##
## LEF for PtnCells ;
## created by Innovus v15.23-s045_1 on Wed Mar 11 08:48:27 2026
##

VERSION 5.8 ;

BUSBITCHARS "[]" ;
DIVIDERCHAR "/" ;

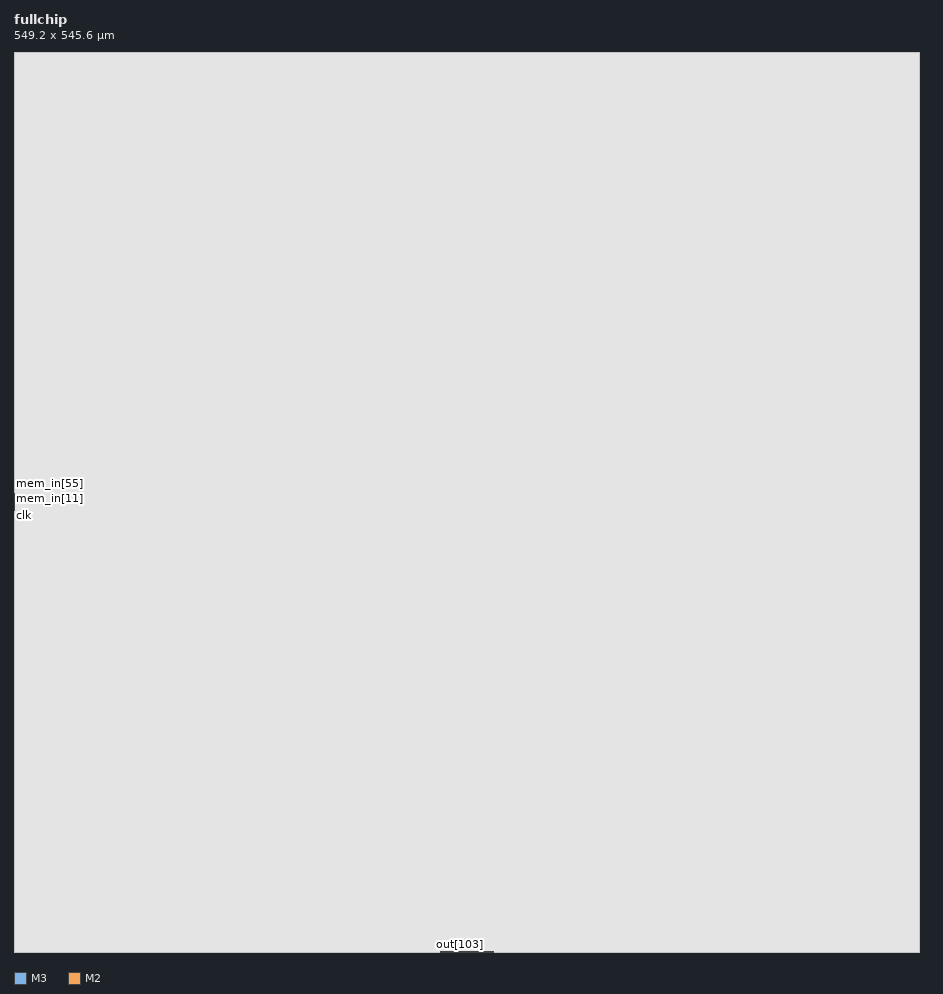
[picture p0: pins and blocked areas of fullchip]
MACRO fullchip
  CLASS BLOCK ;
  SIZE 549.2000 BY 545.6000 ;
  FOREIGN fullchip 0.0000 0.0000 ;
  ORIGIN 0 0 ;
  SYMMETRY X Y R90 ;
  PIN clk
    DIRECTION INPUT ;
    USE SIGNAL ;
    PORT
      LAYER M3 ;
        RECT 0.0000 264.3500 0.5000 264.4500 ;
    END
  END clk
  PIN mem_in[63]
    DIRECTION INPUT ;
    USE SIGNAL ;
    PORT
      LAYER M3 ;
        RECT 0.0000 280.9500 0.5000 281.0500 ;
    END
  END mem_in[63]
  PIN mem_in[62]
    DIRECTION INPUT ;
    USE SIGNAL ;
    PORT
      LAYER M3 ;
        RECT 0.0000 280.7500 0.5000 280.8500 ;
    END
  END mem_in[62]
  PIN mem_in[61]
    DIRECTION INPUT ;
    USE SIGNAL ;
    PORT
      LAYER M3 ;
        RECT 0.0000 280.5500 0.5000 280.6500 ;
    END
  END mem_in[61]
  PIN mem_in[60]
    DIRECTION INPUT ;
    USE SIGNAL ;
    PORT
      LAYER M3 ;
        RECT 0.0000 280.3500 0.5000 280.4500 ;
    END
  END mem_in[60]
  PIN mem_in[59]
    DIRECTION INPUT ;
    USE SIGNAL ;
    PORT
      LAYER M3 ;
        RECT 0.0000 280.1500 0.5000 280.2500 ;
    END
  END mem_in[59]
  PIN mem_in[58]
    DIRECTION INPUT ;
    USE SIGNAL ;
    PORT
      LAYER M3 ;
        RECT 0.0000 279.9500 0.5000 280.0500 ;
    END
  END mem_in[58]
  PIN mem_in[57]
    DIRECTION INPUT ;
    USE SIGNAL ;
    PORT
      LAYER M3 ;
        RECT 0.0000 279.7500 0.5000 279.8500 ;
    END
  END mem_in[57]
  PIN mem_in[56]
    DIRECTION INPUT ;
    USE SIGNAL ;
    PORT
      LAYER M3 ;
        RECT 0.0000 279.5500 0.5000 279.6500 ;
    END
  END mem_in[56]
  PIN mem_in[55]
    DIRECTION INPUT ;
    USE SIGNAL ;
    PORT
      LAYER M3 ;
        RECT 0.0000 279.3500 0.5000 279.4500 ;
    END
  END mem_in[55]
  PIN mem_in[54]
    DIRECTION INPUT ;
    USE SIGNAL ;
    PORT
      LAYER M3 ;
        RECT 0.0000 279.1500 0.5000 279.2500 ;
    END
  END mem_in[54]
  PIN mem_in[53]
    DIRECTION INPUT ;
    USE SIGNAL ;
    PORT
      LAYER M3 ;
        RECT 0.0000 278.9500 0.5000 279.0500 ;
    END
  END mem_in[53]
  PIN mem_in[52]
    DIRECTION INPUT ;
    USE SIGNAL ;
    PORT
      LAYER M3 ;
        RECT 0.0000 278.7500 0.5000 278.8500 ;
    END
  END mem_in[52]
  PIN mem_in[51]
    DIRECTION INPUT ;
    USE SIGNAL ;
    PORT
      LAYER M3 ;
        RECT 0.0000 278.5500 0.5000 278.6500 ;
    END
  END mem_in[51]
  PIN mem_in[50]
    DIRECTION INPUT ;
    USE SIGNAL ;
    PORT
      LAYER M3 ;
        RECT 0.0000 278.3500 0.5000 278.4500 ;
    END
  END mem_in[50]
  PIN mem_in[49]
    DIRECTION INPUT ;
    USE SIGNAL ;
    PORT
      LAYER M3 ;
        RECT 0.0000 278.1500 0.5000 278.2500 ;
    END
  END mem_in[49]
  PIN mem_in[48]
    DIRECTION INPUT ;
    USE SIGNAL ;
    PORT
      LAYER M3 ;
        RECT 0.0000 277.9500 0.5000 278.0500 ;
    END
  END mem_in[48]
  PIN mem_in[47]
    DIRECTION INPUT ;
    USE SIGNAL ;
    PORT
      LAYER M3 ;
        RECT 0.0000 277.7500 0.5000 277.8500 ;
    END
  END mem_in[47]
  PIN mem_in[46]
    DIRECTION INPUT ;
    USE SIGNAL ;
    PORT
      LAYER M3 ;
        RECT 0.0000 277.5500 0.5000 277.6500 ;
    END
  END mem_in[46]
  PIN mem_in[45]
    DIRECTION INPUT ;
    USE SIGNAL ;
    PORT
      LAYER M3 ;
        RECT 0.0000 277.3500 0.5000 277.4500 ;
    END
  END mem_in[45]
  PIN mem_in[44]
    DIRECTION INPUT ;
    USE SIGNAL ;
    PORT
      LAYER M3 ;
        RECT 0.0000 277.1500 0.5000 277.2500 ;
    END
  END mem_in[44]
  PIN mem_in[43]
    DIRECTION INPUT ;
    USE SIGNAL ;
    PORT
      LAYER M3 ;
        RECT 0.0000 276.9500 0.5000 277.0500 ;
    END
  END mem_in[43]
  PIN mem_in[42]
    DIRECTION INPUT ;
    USE SIGNAL ;
    PORT
      LAYER M3 ;
        RECT 0.0000 276.7500 0.5000 276.8500 ;
    END
  END mem_in[42]
  PIN mem_in[41]
    DIRECTION INPUT ;
    USE SIGNAL ;
    PORT
      LAYER M3 ;
        RECT 0.0000 276.5500 0.5000 276.6500 ;
    END
  END mem_in[41]
  PIN mem_in[40]
    DIRECTION INPUT ;
    USE SIGNAL ;
    PORT
      LAYER M3 ;
        RECT 0.0000 276.3500 0.5000 276.4500 ;
    END
  END mem_in[40]
  PIN mem_in[39]
    DIRECTION INPUT ;
    USE SIGNAL ;
    PORT
      LAYER M3 ;
        RECT 0.0000 276.1500 0.5000 276.2500 ;
    END
  END mem_in[39]
  PIN mem_in[38]
    DIRECTION INPUT ;
    USE SIGNAL ;
    PORT
      LAYER M3 ;
        RECT 0.0000 275.9500 0.5000 276.0500 ;
    END
  END mem_in[38]
  PIN mem_in[37]
    DIRECTION INPUT ;
    USE SIGNAL ;
    PORT
      LAYER M3 ;
        RECT 0.0000 275.5500 0.5000 275.6500 ;
    END
  END mem_in[37]
  PIN mem_in[36]
    DIRECTION INPUT ;
    USE SIGNAL ;
    PORT
      LAYER M3 ;
        RECT 0.0000 275.3500 0.5000 275.4500 ;
    END
  END mem_in[36]
  PIN mem_in[35]
    DIRECTION INPUT ;
    USE SIGNAL ;
    PORT
      LAYER M3 ;
        RECT 0.0000 275.1500 0.5000 275.2500 ;
    END
  END mem_in[35]
  PIN mem_in[34]
    DIRECTION INPUT ;
    USE SIGNAL ;
    PORT
      LAYER M3 ;
        RECT 0.0000 274.9500 0.5000 275.0500 ;
    END
  END mem_in[34]
  PIN mem_in[33]
    DIRECTION INPUT ;
    USE SIGNAL ;
    PORT
      LAYER M3 ;
        RECT 0.0000 274.7500 0.5000 274.8500 ;
    END
  END mem_in[33]
  PIN mem_in[32]
    DIRECTION INPUT ;
    USE SIGNAL ;
    PORT
      LAYER M3 ;
        RECT 0.0000 274.5500 0.5000 274.6500 ;
    END
  END mem_in[32]
  PIN mem_in[31]
    DIRECTION INPUT ;
    USE SIGNAL ;
    PORT
      LAYER M3 ;
        RECT 0.0000 274.3500 0.5000 274.4500 ;
    END
  END mem_in[31]
  PIN mem_in[30]
    DIRECTION INPUT ;
    USE SIGNAL ;
    PORT
      LAYER M3 ;
        RECT 0.0000 274.1500 0.5000 274.2500 ;
    END
  END mem_in[30]
  PIN mem_in[29]
    DIRECTION INPUT ;
    USE SIGNAL ;
    PORT
      LAYER M3 ;
        RECT 0.0000 273.9500 0.5000 274.0500 ;
    END
  END mem_in[29]
  PIN mem_in[28]
    DIRECTION INPUT ;
    USE SIGNAL ;
    PORT
      LAYER M3 ;
        RECT 0.0000 273.7500 0.5000 273.8500 ;
    END
  END mem_in[28]
  PIN mem_in[27]
    DIRECTION INPUT ;
    USE SIGNAL ;
    PORT
      LAYER M3 ;
        RECT 0.0000 273.5500 0.5000 273.6500 ;
    END
  END mem_in[27]
  PIN mem_in[26]
    DIRECTION INPUT ;
    USE SIGNAL ;
    PORT
      LAYER M3 ;
        RECT 0.0000 273.3500 0.5000 273.4500 ;
    END
  END mem_in[26]
  PIN mem_in[25]
    DIRECTION INPUT ;
    USE SIGNAL ;
    PORT
      LAYER M3 ;
        RECT 0.0000 273.1500 0.5000 273.2500 ;
    END
  END mem_in[25]
  PIN mem_in[24]
    DIRECTION INPUT ;
    USE SIGNAL ;
    PORT
      LAYER M3 ;
        RECT 0.0000 272.9500 0.5000 273.0500 ;
    END
  END mem_in[24]
  PIN mem_in[23]
    DIRECTION INPUT ;
    USE SIGNAL ;
    PORT
      LAYER M3 ;
        RECT 0.0000 272.7500 0.5000 272.8500 ;
    END
  END mem_in[23]
  PIN mem_in[22]
    DIRECTION INPUT ;
    USE SIGNAL ;
    PORT
      LAYER M3 ;
        RECT 0.0000 272.5500 0.5000 272.6500 ;
    END
  END mem_in[22]
  PIN mem_in[21]
    DIRECTION INPUT ;
    USE SIGNAL ;
    PORT
      LAYER M3 ;
        RECT 0.0000 272.3500 0.5000 272.4500 ;
    END
  END mem_in[21]
  PIN mem_in[20]
    DIRECTION INPUT ;
    USE SIGNAL ;
    PORT
      LAYER M3 ;
        RECT 0.0000 272.1500 0.5000 272.2500 ;
    END
  END mem_in[20]
  PIN mem_in[19]
    DIRECTION INPUT ;
    USE SIGNAL ;
    PORT
      LAYER M3 ;
        RECT 0.0000 271.9500 0.5000 272.0500 ;
    END
  END mem_in[19]
  PIN mem_in[18]
    DIRECTION INPUT ;
    USE SIGNAL ;
    PORT
      LAYER M3 ;
        RECT 0.0000 271.7500 0.5000 271.8500 ;
    END
  END mem_in[18]
  PIN mem_in[17]
    DIRECTION INPUT ;
    USE SIGNAL ;
    PORT
      LAYER M3 ;
        RECT 0.0000 271.5500 0.5000 271.6500 ;
    END
  END mem_in[17]
  PIN mem_in[16]
    DIRECTION INPUT ;
    USE SIGNAL ;
    PORT
      LAYER M3 ;
        RECT 0.0000 271.3500 0.5000 271.4500 ;
    END
  END mem_in[16]
  PIN mem_in[15]
    DIRECTION INPUT ;
    USE SIGNAL ;
    PORT
      LAYER M3 ;
        RECT 0.0000 271.1500 0.5000 271.2500 ;
    END
  END mem_in[15]
  PIN mem_in[14]
    DIRECTION INPUT ;
    USE SIGNAL ;
    PORT
      LAYER M3 ;
        RECT 0.0000 270.9500 0.5000 271.0500 ;
    END
  END mem_in[14]
  PIN mem_in[13]
    DIRECTION INPUT ;
    USE SIGNAL ;
    PORT
      LAYER M3 ;
        RECT 0.0000 270.7500 0.5000 270.8500 ;
    END
  END mem_in[13]
  PIN mem_in[12]
    DIRECTION INPUT ;
    USE SIGNAL ;
    PORT
      LAYER M3 ;
        RECT 0.0000 270.5500 0.5000 270.6500 ;
    END
  END mem_in[12]
  PIN mem_in[11]
    DIRECTION INPUT ;
    USE SIGNAL ;
    PORT
      LAYER M3 ;
        RECT 0.0000 270.3500 0.5000 270.4500 ;
    END
  END mem_in[11]
  PIN mem_in[10]
    DIRECTION INPUT ;
    USE SIGNAL ;
    PORT
      LAYER M3 ;
        RECT 0.0000 270.1500 0.5000 270.2500 ;
    END
  END mem_in[10]
  PIN mem_in[9]
    DIRECTION INPUT ;
    USE SIGNAL ;
    PORT
      LAYER M3 ;
        RECT 0.0000 269.9500 0.5000 270.0500 ;
    END
  END mem_in[9]
  PIN mem_in[8]
    DIRECTION INPUT ;
    USE SIGNAL ;
    PORT
      LAYER M3 ;
        RECT 0.0000 269.7500 0.5000 269.8500 ;
    END
  END mem_in[8]
  PIN mem_in[7]
    DIRECTION INPUT ;
    USE SIGNAL ;
    PORT
      LAYER M3 ;
        RECT 0.0000 269.5500 0.5000 269.6500 ;
    END
  END mem_in[7]
  PIN mem_in[6]
    DIRECTION INPUT ;
    USE SIGNAL ;
    PORT
      LAYER M3 ;
        RECT 0.0000 269.3500 0.5000 269.4500 ;
    END
  END mem_in[6]
  PIN mem_in[5]
    DIRECTION INPUT ;
    USE SIGNAL ;
    PORT
      LAYER M3 ;
        RECT 0.0000 269.1500 0.5000 269.2500 ;
    END
  END mem_in[5]
  PIN mem_in[4]
    DIRECTION INPUT ;
    USE SIGNAL ;
    PORT
      LAYER M3 ;
        RECT 0.0000 268.9500 0.5000 269.0500 ;
    END
  END mem_in[4]
  PIN mem_in[3]
    DIRECTION INPUT ;
    USE SIGNAL ;
    PORT
      LAYER M3 ;
        RECT 0.0000 268.7500 0.5000 268.8500 ;
    END
  END mem_in[3]
  PIN mem_in[2]
    DIRECTION INPUT ;
    USE SIGNAL ;
    PORT
      LAYER M3 ;
        RECT 0.0000 268.5500 0.5000 268.6500 ;
    END
  END mem_in[2]
  PIN mem_in[1]
    DIRECTION INPUT ;
    USE SIGNAL ;
    PORT
      LAYER M3 ;
        RECT 0.0000 268.3500 0.5000 268.4500 ;
    END
  END mem_in[1]
  PIN mem_in[0]
    DIRECTION INPUT ;
    USE SIGNAL ;
    PORT
      LAYER M3 ;
        RECT 0.0000 268.1500 0.5000 268.2500 ;
    END
  END mem_in[0]
  PIN inst[16]
    DIRECTION INPUT ;
    USE SIGNAL ;
    PORT
      LAYER M3 ;
        RECT 0.0000 267.9500 0.5000 268.0500 ;
    END
  END inst[16]
  PIN inst[15]
    DIRECTION INPUT ;
    USE SIGNAL ;
    PORT
      LAYER M3 ;
        RECT 0.0000 267.7500 0.5000 267.8500 ;
    END
  END inst[15]
  PIN inst[14]
    DIRECTION INPUT ;
    USE SIGNAL ;
    PORT
      LAYER M3 ;
        RECT 0.0000 267.5500 0.5000 267.6500 ;
    END
  END inst[14]
  PIN inst[13]
    DIRECTION INPUT ;
    USE SIGNAL ;
    PORT
      LAYER M3 ;
        RECT 0.0000 267.3500 0.5000 267.4500 ;
    END
  END inst[13]
  PIN inst[12]
    DIRECTION INPUT ;
    USE SIGNAL ;
    PORT
      LAYER M3 ;
        RECT 0.0000 267.1500 0.5000 267.2500 ;
    END
  END inst[12]
  PIN inst[11]
    DIRECTION INPUT ;
    USE SIGNAL ;
    PORT
      LAYER M3 ;
        RECT 0.0000 266.9500 0.5000 267.0500 ;
    END
  END inst[11]
  PIN inst[10]
    DIRECTION INPUT ;
    USE SIGNAL ;
    PORT
      LAYER M3 ;
        RECT 0.0000 266.7500 0.5000 266.8500 ;
    END
  END inst[10]
  PIN inst[9]
    DIRECTION INPUT ;
    USE SIGNAL ;
    PORT
      LAYER M3 ;
        RECT 0.0000 266.5500 0.5000 266.6500 ;
    END
  END inst[9]
  PIN inst[8]
    DIRECTION INPUT ;
    USE SIGNAL ;
    PORT
      LAYER M3 ;
        RECT 0.0000 266.3500 0.5000 266.4500 ;
    END
  END inst[8]
  PIN inst[7]
    DIRECTION INPUT ;
    USE SIGNAL ;
    PORT
      LAYER M3 ;
        RECT 0.0000 266.1500 0.5000 266.2500 ;
    END
  END inst[7]
  PIN inst[6]
    DIRECTION INPUT ;
    USE SIGNAL ;
    PORT
      LAYER M3 ;
        RECT 0.0000 265.9500 0.5000 266.0500 ;
    END
  END inst[6]
  PIN inst[5]
    DIRECTION INPUT ;
    USE SIGNAL ;
    PORT
      LAYER M3 ;
        RECT 0.0000 265.7500 0.5000 265.8500 ;
    END
  END inst[5]
  PIN inst[4]
    DIRECTION INPUT ;
    USE SIGNAL ;
    PORT
      LAYER M3 ;
        RECT 0.0000 265.5500 0.5000 265.6500 ;
    END
  END inst[4]
  PIN inst[3]
    DIRECTION INPUT ;
    USE SIGNAL ;
    PORT
      LAYER M3 ;
        RECT 0.0000 265.3500 0.5000 265.4500 ;
    END
  END inst[3]
  PIN inst[2]
    DIRECTION INPUT ;
    USE SIGNAL ;
    PORT
      LAYER M3 ;
        RECT 0.0000 265.1500 0.5000 265.2500 ;
    END
  END inst[2]
  PIN inst[1]
    DIRECTION INPUT ;
    USE SIGNAL ;
    PORT
      LAYER M3 ;
        RECT 0.0000 264.9500 0.5000 265.0500 ;
    END
  END inst[1]
  PIN inst[0]
    DIRECTION INPUT ;
    USE SIGNAL ;
    PORT
      LAYER M3 ;
        RECT 0.0000 264.7500 0.5000 264.8500 ;
    END
  END inst[0]
  PIN reset
    DIRECTION INPUT ;
    USE SIGNAL ;
    PORT
      LAYER M3 ;
        RECT 0.0000 264.5500 0.5000 264.6500 ;
    END
  END reset
  PIN out[159]
    DIRECTION OUTPUT ;
    USE SIGNAL ;
    PORT
      LAYER M2 ;
        RECT 258.8500 0.0000 258.9500 0.5000 ;
    END
  END out[159]
  PIN out[158]
    DIRECTION OUTPUT ;
    USE SIGNAL ;
    PORT
      LAYER M2 ;
        RECT 259.0500 0.0000 259.1500 0.5000 ;
    END
  END out[158]
  PIN out[157]
    DIRECTION OUTPUT ;
    USE SIGNAL ;
    PORT
      LAYER M2 ;
        RECT 259.2500 0.0000 259.3500 0.5000 ;
    END
  END out[157]
  PIN out[156]
    DIRECTION OUTPUT ;
    USE SIGNAL ;
    PORT
      LAYER M2 ;
        RECT 259.4500 0.0000 259.5500 0.5000 ;
    END
  END out[156]
  PIN out[155]
    DIRECTION OUTPUT ;
    USE SIGNAL ;
    PORT
      LAYER M2 ;
        RECT 259.6500 0.0000 259.7500 0.5000 ;
    END
  END out[155]
  PIN out[154]
    DIRECTION OUTPUT ;
    USE SIGNAL ;
    PORT
      LAYER M2 ;
        RECT 259.8500 0.0000 259.9500 0.5000 ;
    END
  END out[154]
  PIN out[153]
    DIRECTION OUTPUT ;
    USE SIGNAL ;
    PORT
      LAYER M2 ;
        RECT 260.0500 0.0000 260.1500 0.5000 ;
    END
  END out[153]
  PIN out[152]
    DIRECTION OUTPUT ;
    USE SIGNAL ;
    PORT
      LAYER M2 ;
        RECT 260.2500 0.0000 260.3500 0.5000 ;
    END
  END out[152]
  PIN out[151]
    DIRECTION OUTPUT ;
    USE SIGNAL ;
    PORT
      LAYER M2 ;
        RECT 260.4500 0.0000 260.5500 0.5000 ;
    END
  END out[151]
  PIN out[150]
    DIRECTION OUTPUT ;
    USE SIGNAL ;
    PORT
      LAYER M2 ;
        RECT 260.6500 0.0000 260.7500 0.5000 ;
    END
  END out[150]
  PIN out[149]
    DIRECTION OUTPUT ;
    USE SIGNAL ;
    PORT
      LAYER M2 ;
        RECT 260.8500 0.0000 260.9500 0.5000 ;
    END
  END out[149]
  PIN out[148]
    DIRECTION OUTPUT ;
    USE SIGNAL ;
    PORT
      LAYER M2 ;
        RECT 261.0500 0.0000 261.1500 0.5000 ;
    END
  END out[148]
  PIN out[147]
    DIRECTION OUTPUT ;
    USE SIGNAL ;
    PORT
      LAYER M2 ;
        RECT 261.2500 0.0000 261.3500 0.5000 ;
    END
  END out[147]
  PIN out[146]
    DIRECTION OUTPUT ;
    USE SIGNAL ;
    PORT
      LAYER M2 ;
        RECT 261.4500 0.0000 261.5500 0.5000 ;
    END
  END out[146]
  PIN out[145]
    DIRECTION OUTPUT ;
    USE SIGNAL ;
    PORT
      LAYER M2 ;
        RECT 261.6500 0.0000 261.7500 0.5000 ;
    END
  END out[145]
  PIN out[144]
    DIRECTION OUTPUT ;
    USE SIGNAL ;
    PORT
      LAYER M2 ;
        RECT 261.8500 0.0000 261.9500 0.5000 ;
    END
  END out[144]
  PIN out[143]
    DIRECTION OUTPUT ;
    USE SIGNAL ;
    PORT
      LAYER M2 ;
        RECT 262.0500 0.0000 262.1500 0.5000 ;
    END
  END out[143]
  PIN out[142]
    DIRECTION OUTPUT ;
    USE SIGNAL ;
    PORT
      LAYER M2 ;
        RECT 262.2500 0.0000 262.3500 0.5000 ;
    END
  END out[142]
  PIN out[141]
    DIRECTION OUTPUT ;
    USE SIGNAL ;
    PORT
      LAYER M2 ;
        RECT 262.4500 0.0000 262.5500 0.5000 ;
    END
  END out[141]
  PIN out[140]
    DIRECTION OUTPUT ;
    USE SIGNAL ;
    PORT
      LAYER M2 ;
        RECT 262.6500 0.0000 262.7500 0.5000 ;
    END
  END out[140]
  PIN out[139]
    DIRECTION OUTPUT ;
    USE SIGNAL ;
    PORT
      LAYER M2 ;
        RECT 262.8500 0.0000 262.9500 0.5000 ;
    END
  END out[139]
  PIN out[138]
    DIRECTION OUTPUT ;
    USE SIGNAL ;
    PORT
      LAYER M2 ;
        RECT 263.0500 0.0000 263.1500 0.5000 ;
    END
  END out[138]
  PIN out[137]
    DIRECTION OUTPUT ;
    USE SIGNAL ;
    PORT
      LAYER M2 ;
        RECT 263.2500 0.0000 263.3500 0.5000 ;
    END
  END out[137]
  PIN out[136]
    DIRECTION OUTPUT ;
    USE SIGNAL ;
    PORT
      LAYER M2 ;
        RECT 263.4500 0.0000 263.5500 0.5000 ;
    END
  END out[136]
  PIN out[135]
    DIRECTION OUTPUT ;
    USE SIGNAL ;
    PORT
      LAYER M2 ;
        RECT 263.6500 0.0000 263.7500 0.5000 ;
    END
  END out[135]
  PIN out[134]
    DIRECTION OUTPUT ;
    USE SIGNAL ;
    PORT
      LAYER M2 ;
        RECT 263.8500 0.0000 263.9500 0.5000 ;
    END
  END out[134]
  PIN out[133]
    DIRECTION OUTPUT ;
    USE SIGNAL ;
    PORT
      LAYER M2 ;
        RECT 264.0500 0.0000 264.1500 0.5000 ;
    END
  END out[133]
  PIN out[132]
    DIRECTION OUTPUT ;
    USE SIGNAL ;
    PORT
      LAYER M2 ;
        RECT 264.2500 0.0000 264.3500 0.5000 ;
    END
  END out[132]
  PIN out[131]
    DIRECTION OUTPUT ;
    USE SIGNAL ;
    PORT
      LAYER M2 ;
        RECT 264.4500 0.0000 264.5500 0.5000 ;
    END
  END out[131]
  PIN out[130]
    DIRECTION OUTPUT ;
    USE SIGNAL ;
    PORT
      LAYER M2 ;
        RECT 264.6500 0.0000 264.7500 0.5000 ;
    END
  END out[130]
  PIN out[129]
    DIRECTION OUTPUT ;
    USE SIGNAL ;
    PORT
      LAYER M2 ;
        RECT 264.8500 0.0000 264.9500 0.5000 ;
    END
  END out[129]
  PIN out[128]
    DIRECTION OUTPUT ;
    USE SIGNAL ;
    PORT
      LAYER M2 ;
        RECT 265.0500 0.0000 265.1500 0.5000 ;
    END
  END out[128]
  PIN out[127]
    DIRECTION OUTPUT ;
    USE SIGNAL ;
    PORT
      LAYER M2 ;
        RECT 265.2500 0.0000 265.3500 0.5000 ;
    END
  END out[127]
  PIN out[126]
    DIRECTION OUTPUT ;
    USE SIGNAL ;
    PORT
      LAYER M2 ;
        RECT 265.4500 0.0000 265.5500 0.5000 ;
    END
  END out[126]
  PIN out[125]
    DIRECTION OUTPUT ;
    USE SIGNAL ;
    PORT
      LAYER M2 ;
        RECT 265.6500 0.0000 265.7500 0.5000 ;
    END
  END out[125]
  PIN out[124]
    DIRECTION OUTPUT ;
    USE SIGNAL ;
    PORT
      LAYER M2 ;
        RECT 265.8500 0.0000 265.9500 0.5000 ;
    END
  END out[124]
  PIN out[123]
    DIRECTION OUTPUT ;
    USE SIGNAL ;
    PORT
      LAYER M2 ;
        RECT 266.0500 0.0000 266.1500 0.5000 ;
    END
  END out[123]
  PIN out[122]
    DIRECTION OUTPUT ;
    USE SIGNAL ;
    PORT
      LAYER M2 ;
        RECT 266.2500 0.0000 266.3500 0.5000 ;
    END
  END out[122]
  PIN out[121]
    DIRECTION OUTPUT ;
    USE SIGNAL ;
    PORT
      LAYER M2 ;
        RECT 266.4500 0.0000 266.5500 0.5000 ;
    END
  END out[121]
  PIN out[120]
    DIRECTION OUTPUT ;
    USE SIGNAL ;
    PORT
      LAYER M2 ;
        RECT 266.6500 0.0000 266.7500 0.5000 ;
    END
  END out[120]
  PIN out[119]
    DIRECTION OUTPUT ;
    USE SIGNAL ;
    PORT
      LAYER M2 ;
        RECT 266.8500 0.0000 266.9500 0.5000 ;
    END
  END out[119]
  PIN out[118]
    DIRECTION OUTPUT ;
    USE SIGNAL ;
    PORT
      LAYER M2 ;
        RECT 267.0500 0.0000 267.1500 0.5000 ;
    END
  END out[118]
  PIN out[117]
    DIRECTION OUTPUT ;
    USE SIGNAL ;
    PORT
      LAYER M2 ;
        RECT 267.2500 0.0000 267.3500 0.5000 ;
    END
  END out[117]
  PIN out[116]
    DIRECTION OUTPUT ;
    USE SIGNAL ;
    PORT
      LAYER M2 ;
        RECT 267.4500 0.0000 267.5500 0.5000 ;
    END
  END out[116]
  PIN out[115]
    DIRECTION OUTPUT ;
    USE SIGNAL ;
    PORT
      LAYER M2 ;
        RECT 267.6500 0.0000 267.7500 0.5000 ;
    END
  END out[115]
  PIN out[114]
    DIRECTION OUTPUT ;
    USE SIGNAL ;
    PORT
      LAYER M2 ;
        RECT 267.8500 0.0000 267.9500 0.5000 ;
    END
  END out[114]
  PIN out[113]
    DIRECTION OUTPUT ;
    USE SIGNAL ;
    PORT
      LAYER M2 ;
        RECT 268.0500 0.0000 268.1500 0.5000 ;
    END
  END out[113]
  PIN out[112]
    DIRECTION OUTPUT ;
    USE SIGNAL ;
    PORT
      LAYER M2 ;
        RECT 268.2500 0.0000 268.3500 0.5000 ;
    END
  END out[112]
  PIN out[111]
    DIRECTION OUTPUT ;
    USE SIGNAL ;
    PORT
      LAYER M2 ;
        RECT 268.4500 0.0000 268.5500 0.5000 ;
    END
  END out[111]
  PIN out[110]
    DIRECTION OUTPUT ;
    USE SIGNAL ;
    PORT
      LAYER M2 ;
        RECT 268.6500 0.0000 268.7500 0.5000 ;
    END
  END out[110]
  PIN out[109]
    DIRECTION OUTPUT ;
    USE SIGNAL ;
    PORT
      LAYER M2 ;
        RECT 268.8500 0.0000 268.9500 0.5000 ;
    END
  END out[109]
  PIN out[108]
    DIRECTION OUTPUT ;
    USE SIGNAL ;
    PORT
      LAYER M2 ;
        RECT 269.0500 0.0000 269.1500 0.5000 ;
    END
  END out[108]
  PIN out[107]
    DIRECTION OUTPUT ;
    USE SIGNAL ;
    PORT
      LAYER M2 ;
        RECT 269.2500 0.0000 269.3500 0.5000 ;
    END
  END out[107]
  PIN out[106]
    DIRECTION OUTPUT ;
    USE SIGNAL ;
    PORT
      LAYER M2 ;
        RECT 269.4500 0.0000 269.5500 0.5000 ;
    END
  END out[106]
  PIN out[105]
    DIRECTION OUTPUT ;
    USE SIGNAL ;
    PORT
      LAYER M2 ;
        RECT 269.6500 0.0000 269.7500 0.5000 ;
    END
  END out[105]
  PIN out[104]
    DIRECTION OUTPUT ;
    USE SIGNAL ;
    PORT
      LAYER M2 ;
        RECT 269.8500 0.0000 269.9500 0.5000 ;
    END
  END out[104]
  PIN out[103]
    DIRECTION OUTPUT ;
    USE SIGNAL ;
    PORT
      LAYER M2 ;
        RECT 270.0500 0.0000 270.1500 0.5000 ;
    END
  END out[103]
  PIN out[102]
    DIRECTION OUTPUT ;
    USE SIGNAL ;
    PORT
      LAYER M2 ;
        RECT 270.2500 0.0000 270.3500 0.5000 ;
    END
  END out[102]
  PIN out[101]
    DIRECTION OUTPUT ;
    USE SIGNAL ;
    PORT
      LAYER M2 ;
        RECT 270.4500 0.0000 270.5500 0.5000 ;
    END
  END out[101]
  PIN out[100]
    DIRECTION OUTPUT ;
    USE SIGNAL ;
    PORT
      LAYER M2 ;
        RECT 270.6500 0.0000 270.7500 0.5000 ;
    END
  END out[100]
  PIN out[99]
    DIRECTION OUTPUT ;
    USE SIGNAL ;
    PORT
      LAYER M2 ;
        RECT 270.8500 0.0000 270.9500 0.5000 ;
    END
  END out[99]
  PIN out[98]
    DIRECTION OUTPUT ;
    USE SIGNAL ;
    PORT
      LAYER M2 ;
        RECT 271.0500 0.0000 271.1500 0.5000 ;
    END
  END out[98]
  PIN out[97]
    DIRECTION OUTPUT ;
    USE SIGNAL ;
    PORT
      LAYER M2 ;
        RECT 271.2500 0.0000 271.3500 0.5000 ;
    END
  END out[97]
  PIN out[96]
    DIRECTION OUTPUT ;
    USE SIGNAL ;
    PORT
      LAYER M2 ;
        RECT 271.4500 0.0000 271.5500 0.5000 ;
    END
  END out[96]
  PIN out[95]
    DIRECTION OUTPUT ;
    USE SIGNAL ;
    PORT
      LAYER M2 ;
        RECT 271.6500 0.0000 271.7500 0.5000 ;
    END
  END out[95]
  PIN out[94]
    DIRECTION OUTPUT ;
    USE SIGNAL ;
    PORT
      LAYER M2 ;
        RECT 271.8500 0.0000 271.9500 0.5000 ;
    END
  END out[94]
  PIN out[93]
    DIRECTION OUTPUT ;
    USE SIGNAL ;
    PORT
      LAYER M2 ;
        RECT 272.0500 0.0000 272.1500 0.5000 ;
    END
  END out[93]
  PIN out[92]
    DIRECTION OUTPUT ;
    USE SIGNAL ;
    PORT
      LAYER M2 ;
        RECT 272.2500 0.0000 272.3500 0.5000 ;
    END
  END out[92]
  PIN out[91]
    DIRECTION OUTPUT ;
    USE SIGNAL ;
    PORT
      LAYER M2 ;
        RECT 272.4500 0.0000 272.5500 0.5000 ;
    END
  END out[91]
  PIN out[90]
    DIRECTION OUTPUT ;
    USE SIGNAL ;
    PORT
      LAYER M2 ;
        RECT 272.6500 0.0000 272.7500 0.5000 ;
    END
  END out[90]
  PIN out[89]
    DIRECTION OUTPUT ;
    USE SIGNAL ;
    PORT
      LAYER M2 ;
        RECT 272.8500 0.0000 272.9500 0.5000 ;
    END
  END out[89]
  PIN out[88]
    DIRECTION OUTPUT ;
    USE SIGNAL ;
    PORT
      LAYER M2 ;
        RECT 273.0500 0.0000 273.1500 0.5000 ;
    END
  END out[88]
  PIN out[87]
    DIRECTION OUTPUT ;
    USE SIGNAL ;
    PORT
      LAYER M2 ;
        RECT 273.2500 0.0000 273.3500 0.5000 ;
    END
  END out[87]
  PIN out[86]
    DIRECTION OUTPUT ;
    USE SIGNAL ;
    PORT
      LAYER M2 ;
        RECT 273.4500 0.0000 273.5500 0.5000 ;
    END
  END out[86]
  PIN out[85]
    DIRECTION OUTPUT ;
    USE SIGNAL ;
    PORT
      LAYER M2 ;
        RECT 273.6500 0.0000 273.7500 0.5000 ;
    END
  END out[85]
  PIN out[84]
    DIRECTION OUTPUT ;
    USE SIGNAL ;
    PORT
      LAYER M2 ;
        RECT 273.8500 0.0000 273.9500 0.5000 ;
    END
  END out[84]
  PIN out[83]
    DIRECTION OUTPUT ;
    USE SIGNAL ;
    PORT
      LAYER M2 ;
        RECT 274.0500 0.0000 274.1500 0.5000 ;
    END
  END out[83]
  PIN out[82]
    DIRECTION OUTPUT ;
    USE SIGNAL ;
    PORT
      LAYER M2 ;
        RECT 274.2500 0.0000 274.3500 0.5000 ;
    END
  END out[82]
  PIN out[81]
    DIRECTION OUTPUT ;
    USE SIGNAL ;
    PORT
      LAYER M2 ;
        RECT 274.4500 0.0000 274.5500 0.5000 ;
    END
  END out[81]
  PIN out[80]
    DIRECTION OUTPUT ;
    USE SIGNAL ;
    PORT
      LAYER M2 ;
        RECT 274.6500 0.0000 274.7500 0.5000 ;
    END
  END out[80]
  PIN out[79]
    DIRECTION OUTPUT ;
    USE SIGNAL ;
    PORT
      LAYER M2 ;
        RECT 274.8500 0.0000 274.9500 0.5000 ;
    END
  END out[79]
  PIN out[78]
    DIRECTION OUTPUT ;
    USE SIGNAL ;
    PORT
      LAYER M2 ;
        RECT 275.0500 0.0000 275.1500 0.5000 ;
    END
  END out[78]
  PIN out[77]
    DIRECTION OUTPUT ;
    USE SIGNAL ;
    PORT
      LAYER M2 ;
        RECT 275.2500 0.0000 275.3500 0.5000 ;
    END
  END out[77]
  PIN out[76]
    DIRECTION OUTPUT ;
    USE SIGNAL ;
    PORT
      LAYER M2 ;
        RECT 275.4500 0.0000 275.5500 0.5000 ;
    END
  END out[76]
  PIN out[75]
    DIRECTION OUTPUT ;
    USE SIGNAL ;
    PORT
      LAYER M2 ;
        RECT 275.6500 0.0000 275.7500 0.5000 ;
    END
  END out[75]
  PIN out[74]
    DIRECTION OUTPUT ;
    USE SIGNAL ;
    PORT
      LAYER M2 ;
        RECT 275.8500 0.0000 275.9500 0.5000 ;
    END
  END out[74]
  PIN out[73]
    DIRECTION OUTPUT ;
    USE SIGNAL ;
    PORT
      LAYER M2 ;
        RECT 276.0500 0.0000 276.1500 0.5000 ;
    END
  END out[73]
  PIN out[72]
    DIRECTION OUTPUT ;
    USE SIGNAL ;
    PORT
      LAYER M2 ;
        RECT 276.2500 0.0000 276.3500 0.5000 ;
    END
  END out[72]
  PIN out[71]
    DIRECTION OUTPUT ;
    USE SIGNAL ;
    PORT
      LAYER M2 ;
        RECT 276.4500 0.0000 276.5500 0.5000 ;
    END
  END out[71]
  PIN out[70]
    DIRECTION OUTPUT ;
    USE SIGNAL ;
    PORT
      LAYER M2 ;
        RECT 276.6500 0.0000 276.7500 0.5000 ;
    END
  END out[70]
  PIN out[69]
    DIRECTION OUTPUT ;
    USE SIGNAL ;
    PORT
      LAYER M2 ;
        RECT 276.8500 0.0000 276.9500 0.5000 ;
    END
  END out[69]
  PIN out[68]
    DIRECTION OUTPUT ;
    USE SIGNAL ;
    PORT
      LAYER M2 ;
        RECT 277.0500 0.0000 277.1500 0.5000 ;
    END
  END out[68]
  PIN out[67]
    DIRECTION OUTPUT ;
    USE SIGNAL ;
    PORT
      LAYER M2 ;
        RECT 277.2500 0.0000 277.3500 0.5000 ;
    END
  END out[67]
  PIN out[66]
    DIRECTION OUTPUT ;
    USE SIGNAL ;
    PORT
      LAYER M2 ;
        RECT 277.4500 0.0000 277.5500 0.5000 ;
    END
  END out[66]
  PIN out[65]
    DIRECTION OUTPUT ;
    USE SIGNAL ;
    PORT
      LAYER M2 ;
        RECT 277.6500 0.0000 277.7500 0.5000 ;
    END
  END out[65]
  PIN out[64]
    DIRECTION OUTPUT ;
    USE SIGNAL ;
    PORT
      LAYER M2 ;
        RECT 277.8500 0.0000 277.9500 0.5000 ;
    END
  END out[64]
  PIN out[63]
    DIRECTION OUTPUT ;
    USE SIGNAL ;
    PORT
      LAYER M2 ;
        RECT 278.0500 0.0000 278.1500 0.5000 ;
    END
  END out[63]
  PIN out[62]
    DIRECTION OUTPUT ;
    USE SIGNAL ;
    PORT
      LAYER M2 ;
        RECT 278.2500 0.0000 278.3500 0.5000 ;
    END
  END out[62]
  PIN out[61]
    DIRECTION OUTPUT ;
    USE SIGNAL ;
    PORT
      LAYER M2 ;
        RECT 278.4500 0.0000 278.5500 0.5000 ;
    END
  END out[61]
  PIN out[60]
    DIRECTION OUTPUT ;
    USE SIGNAL ;
    PORT
      LAYER M2 ;
        RECT 278.6500 0.0000 278.7500 0.5000 ;
    END
  END out[60]
  PIN out[59]
    DIRECTION OUTPUT ;
    USE SIGNAL ;
    PORT
      LAYER M2 ;
        RECT 278.8500 0.0000 278.9500 0.5000 ;
    END
  END out[59]
  PIN out[58]
    DIRECTION OUTPUT ;
    USE SIGNAL ;
    PORT
      LAYER M2 ;
        RECT 279.0500 0.0000 279.1500 0.5000 ;
    END
  END out[58]
  PIN out[57]
    DIRECTION OUTPUT ;
    USE SIGNAL ;
    PORT
      LAYER M2 ;
        RECT 279.2500 0.0000 279.3500 0.5000 ;
    END
  END out[57]
  PIN out[56]
    DIRECTION OUTPUT ;
    USE SIGNAL ;
    PORT
      LAYER M2 ;
        RECT 279.4500 0.0000 279.5500 0.5000 ;
    END
  END out[56]
  PIN out[55]
    DIRECTION OUTPUT ;
    USE SIGNAL ;
    PORT
      LAYER M2 ;
        RECT 279.6500 0.0000 279.7500 0.5000 ;
    END
  END out[55]
  PIN out[54]
    DIRECTION OUTPUT ;
    USE SIGNAL ;
    PORT
      LAYER M2 ;
        RECT 279.8500 0.0000 279.9500 0.5000 ;
    END
  END out[54]
  PIN out[53]
    DIRECTION OUTPUT ;
    USE SIGNAL ;
    PORT
      LAYER M2 ;
        RECT 280.0500 0.0000 280.1500 0.5000 ;
    END
  END out[53]
  PIN out[52]
    DIRECTION OUTPUT ;
    USE SIGNAL ;
    PORT
      LAYER M2 ;
        RECT 280.2500 0.0000 280.3500 0.5000 ;
    END
  END out[52]
  PIN out[51]
    DIRECTION OUTPUT ;
    USE SIGNAL ;
    PORT
      LAYER M2 ;
        RECT 280.4500 0.0000 280.5500 0.5000 ;
    END
  END out[51]
  PIN out[50]
    DIRECTION OUTPUT ;
    USE SIGNAL ;
    PORT
      LAYER M2 ;
        RECT 280.6500 0.0000 280.7500 0.5000 ;
    END
  END out[50]
  PIN out[49]
    DIRECTION OUTPUT ;
    USE SIGNAL ;
    PORT
      LAYER M2 ;
        RECT 280.8500 0.0000 280.9500 0.5000 ;
    END
  END out[49]
  PIN out[48]
    DIRECTION OUTPUT ;
    USE SIGNAL ;
    PORT
      LAYER M2 ;
        RECT 281.0500 0.0000 281.1500 0.5000 ;
    END
  END out[48]
  PIN out[47]
    DIRECTION OUTPUT ;
    USE SIGNAL ;
    PORT
      LAYER M2 ;
        RECT 281.2500 0.0000 281.3500 0.5000 ;
    END
  END out[47]
  PIN out[46]
    DIRECTION OUTPUT ;
    USE SIGNAL ;
    PORT
      LAYER M2 ;
        RECT 281.4500 0.0000 281.5500 0.5000 ;
    END
  END out[46]
  PIN out[45]
    DIRECTION OUTPUT ;
    USE SIGNAL ;
    PORT
      LAYER M2 ;
        RECT 281.6500 0.0000 281.7500 0.5000 ;
    END
  END out[45]
  PIN out[44]
    DIRECTION OUTPUT ;
    USE SIGNAL ;
    PORT
      LAYER M2 ;
        RECT 281.8500 0.0000 281.9500 0.5000 ;
    END
  END out[44]
  PIN out[43]
    DIRECTION OUTPUT ;
    USE SIGNAL ;
    PORT
      LAYER M2 ;
        RECT 282.0500 0.0000 282.1500 0.5000 ;
    END
  END out[43]
  PIN out[42]
    DIRECTION OUTPUT ;
    USE SIGNAL ;
    PORT
      LAYER M2 ;
        RECT 282.2500 0.0000 282.3500 0.5000 ;
    END
  END out[42]
  PIN out[41]
    DIRECTION OUTPUT ;
    USE SIGNAL ;
    PORT
      LAYER M2 ;
        RECT 282.4500 0.0000 282.5500 0.5000 ;
    END
  END out[41]
  PIN out[40]
    DIRECTION OUTPUT ;
    USE SIGNAL ;
    PORT
      LAYER M2 ;
        RECT 282.6500 0.0000 282.7500 0.5000 ;
    END
  END out[40]
  PIN out[39]
    DIRECTION OUTPUT ;
    USE SIGNAL ;
    PORT
      LAYER M2 ;
        RECT 282.8500 0.0000 282.9500 0.5000 ;
    END
  END out[39]
  PIN out[38]
    DIRECTION OUTPUT ;
    USE SIGNAL ;
    PORT
      LAYER M2 ;
        RECT 283.0500 0.0000 283.1500 0.5000 ;
    END
  END out[38]
  PIN out[37]
    DIRECTION OUTPUT ;
    USE SIGNAL ;
    PORT
      LAYER M2 ;
        RECT 283.2500 0.0000 283.3500 0.5000 ;
    END
  END out[37]
  PIN out[36]
    DIRECTION OUTPUT ;
    USE SIGNAL ;
    PORT
      LAYER M2 ;
        RECT 283.4500 0.0000 283.5500 0.5000 ;
    END
  END out[36]
  PIN out[35]
    DIRECTION OUTPUT ;
    USE SIGNAL ;
    PORT
      LAYER M2 ;
        RECT 283.6500 0.0000 283.7500 0.5000 ;
    END
  END out[35]
  PIN out[34]
    DIRECTION OUTPUT ;
    USE SIGNAL ;
    PORT
      LAYER M2 ;
        RECT 283.8500 0.0000 283.9500 0.5000 ;
    END
  END out[34]
  PIN out[33]
    DIRECTION OUTPUT ;
    USE SIGNAL ;
    PORT
      LAYER M2 ;
        RECT 284.0500 0.0000 284.1500 0.5000 ;
    END
  END out[33]
  PIN out[32]
    DIRECTION OUTPUT ;
    USE SIGNAL ;
    PORT
      LAYER M2 ;
        RECT 284.2500 0.0000 284.3500 0.5000 ;
    END
  END out[32]
  PIN out[31]
    DIRECTION OUTPUT ;
    USE SIGNAL ;
    PORT
      LAYER M2 ;
        RECT 284.4500 0.0000 284.5500 0.5000 ;
    END
  END out[31]
  PIN out[30]
    DIRECTION OUTPUT ;
    USE SIGNAL ;
    PORT
      LAYER M2 ;
        RECT 284.6500 0.0000 284.7500 0.5000 ;
    END
  END out[30]
  PIN out[29]
    DIRECTION OUTPUT ;
    USE SIGNAL ;
    PORT
      LAYER M2 ;
        RECT 284.8500 0.0000 284.9500 0.5000 ;
    END
  END out[29]
  PIN out[28]
    DIRECTION OUTPUT ;
    USE SIGNAL ;
    PORT
      LAYER M2 ;
        RECT 285.0500 0.0000 285.1500 0.5000 ;
    END
  END out[28]
  PIN out[27]
    DIRECTION OUTPUT ;
    USE SIGNAL ;
    PORT
      LAYER M2 ;
        RECT 285.2500 0.0000 285.3500 0.5000 ;
    END
  END out[27]
  PIN out[26]
    DIRECTION OUTPUT ;
    USE SIGNAL ;
    PORT
      LAYER M2 ;
        RECT 285.4500 0.0000 285.5500 0.5000 ;
    END
  END out[26]
  PIN out[25]
    DIRECTION OUTPUT ;
    USE SIGNAL ;
    PORT
      LAYER M2 ;
        RECT 285.6500 0.0000 285.7500 0.5000 ;
    END
  END out[25]
  PIN out[24]
    DIRECTION OUTPUT ;
    USE SIGNAL ;
    PORT
      LAYER M2 ;
        RECT 285.8500 0.0000 285.9500 0.5000 ;
    END
  END out[24]
  PIN out[23]
    DIRECTION OUTPUT ;
    USE SIGNAL ;
    PORT
      LAYER M2 ;
        RECT 286.0500 0.0000 286.1500 0.5000 ;
    END
  END out[23]
  PIN out[22]
    DIRECTION OUTPUT ;
    USE SIGNAL ;
    PORT
      LAYER M2 ;
        RECT 286.2500 0.0000 286.3500 0.5000 ;
    END
  END out[22]
  PIN out[21]
    DIRECTION OUTPUT ;
    USE SIGNAL ;
    PORT
      LAYER M2 ;
        RECT 286.4500 0.0000 286.5500 0.5000 ;
    END
  END out[21]
  PIN out[20]
    DIRECTION OUTPUT ;
    USE SIGNAL ;
    PORT
      LAYER M2 ;
        RECT 286.6500 0.0000 286.7500 0.5000 ;
    END
  END out[20]
  PIN out[19]
    DIRECTION OUTPUT ;
    USE SIGNAL ;
    PORT
      LAYER M2 ;
        RECT 286.8500 0.0000 286.9500 0.5000 ;
    END
  END out[19]
  PIN out[18]
    DIRECTION OUTPUT ;
    USE SIGNAL ;
    PORT
      LAYER M2 ;
        RECT 287.0500 0.0000 287.1500 0.5000 ;
    END
  END out[18]
  PIN out[17]
    DIRECTION OUTPUT ;
    USE SIGNAL ;
    PORT
      LAYER M2 ;
        RECT 287.2500 0.0000 287.3500 0.5000 ;
    END
  END out[17]
  PIN out[16]
    DIRECTION OUTPUT ;
    USE SIGNAL ;
    PORT
      LAYER M2 ;
        RECT 287.4500 0.0000 287.5500 0.5000 ;
    END
  END out[16]
  PIN out[15]
    DIRECTION OUTPUT ;
    USE SIGNAL ;
    PORT
      LAYER M2 ;
        RECT 287.6500 0.0000 287.7500 0.5000 ;
    END
  END out[15]
  PIN out[14]
    DIRECTION OUTPUT ;
    USE SIGNAL ;
    PORT
      LAYER M2 ;
        RECT 287.8500 0.0000 287.9500 0.5000 ;
    END
  END out[14]
  PIN out[13]
    DIRECTION OUTPUT ;
    USE SIGNAL ;
    PORT
      LAYER M2 ;
        RECT 288.0500 0.0000 288.1500 0.5000 ;
    END
  END out[13]
  PIN out[12]
    DIRECTION OUTPUT ;
    USE SIGNAL ;
    PORT
      LAYER M2 ;
        RECT 288.2500 0.0000 288.3500 0.5000 ;
    END
  END out[12]
  PIN out[11]
    DIRECTION OUTPUT ;
    USE SIGNAL ;
    PORT
      LAYER M2 ;
        RECT 288.4500 0.0000 288.5500 0.5000 ;
    END
  END out[11]
  PIN out[10]
    DIRECTION OUTPUT ;
    USE SIGNAL ;
    PORT
      LAYER M2 ;
        RECT 288.6500 0.0000 288.7500 0.5000 ;
    END
  END out[10]
  PIN out[9]
    DIRECTION OUTPUT ;
    USE SIGNAL ;
    PORT
      LAYER M2 ;
        RECT 288.8500 0.0000 288.9500 0.5000 ;
    END
  END out[9]
  PIN out[8]
    DIRECTION OUTPUT ;
    USE SIGNAL ;
    PORT
      LAYER M2 ;
        RECT 289.0500 0.0000 289.1500 0.5000 ;
    END
  END out[8]
  PIN out[7]
    DIRECTION OUTPUT ;
    USE SIGNAL ;
    PORT
      LAYER M2 ;
        RECT 289.2500 0.0000 289.3500 0.5000 ;
    END
  END out[7]
  PIN out[6]
    DIRECTION OUTPUT ;
    USE SIGNAL ;
    PORT
      LAYER M2 ;
        RECT 289.4500 0.0000 289.5500 0.5000 ;
    END
  END out[6]
  PIN out[5]
    DIRECTION OUTPUT ;
    USE SIGNAL ;
    PORT
      LAYER M2 ;
        RECT 289.6500 0.0000 289.7500 0.5000 ;
    END
  END out[5]
  PIN out[4]
    DIRECTION OUTPUT ;
    USE SIGNAL ;
    PORT
      LAYER M2 ;
        RECT 289.8500 0.0000 289.9500 0.5000 ;
    END
  END out[4]
  PIN out[3]
    DIRECTION OUTPUT ;
    USE SIGNAL ;
    PORT
      LAYER M2 ;
        RECT 290.0500 0.0000 290.1500 0.5000 ;
    END
  END out[3]
  PIN out[2]
    DIRECTION OUTPUT ;
    USE SIGNAL ;
    PORT
      LAYER M2 ;
        RECT 290.2500 0.0000 290.3500 0.5000 ;
    END
  END out[2]
  PIN out[1]
    DIRECTION OUTPUT ;
    USE SIGNAL ;
    PORT
      LAYER M2 ;
        RECT 290.4500 0.0000 290.5500 0.5000 ;
    END
  END out[1]
  PIN out[0]
    DIRECTION OUTPUT ;
    USE SIGNAL ;
    PORT
      LAYER M2 ;
        RECT 290.6500 0.0000 290.7500 0.5000 ;
    END
  END out[0]
  OBS
    LAYER M1 ;
      RECT 0.0000 0.0000 549.2000 545.6000 ;
    LAYER M2 ;
      RECT 0.0000 0.6000 549.2000 545.6000 ;
      RECT 290.8500 0.0000 549.2000 0.6000 ;
      RECT 0.0000 0.0000 258.7500 0.6000 ;
    LAYER M3 ;
      RECT 0.0000 281.1500 549.2000 545.6000 ;
      RECT 0.6000 275.8500 549.2000 281.1500 ;
      RECT 0.0000 275.7500 549.2000 275.8500 ;
      RECT 0.6000 264.2500 549.2000 275.7500 ;
      RECT 0.0000 0.0000 549.2000 264.2500 ;
    LAYER M4 ;
      RECT 0.0000 0.0000 549.2000 545.6000 ;
    LAYER M5 ;
      RECT 0.0000 0.0000 549.2000 545.6000 ;
    LAYER M6 ;
      RECT 0.0000 0.0000 549.2000 545.6000 ;
    LAYER M7 ;
      RECT 0.0000 0.0000 549.2000 545.6000 ;
    LAYER M8 ;
      RECT 0.0000 0.0000 549.2000 545.6000 ;
  END
END fullchip

END LIBRARY
